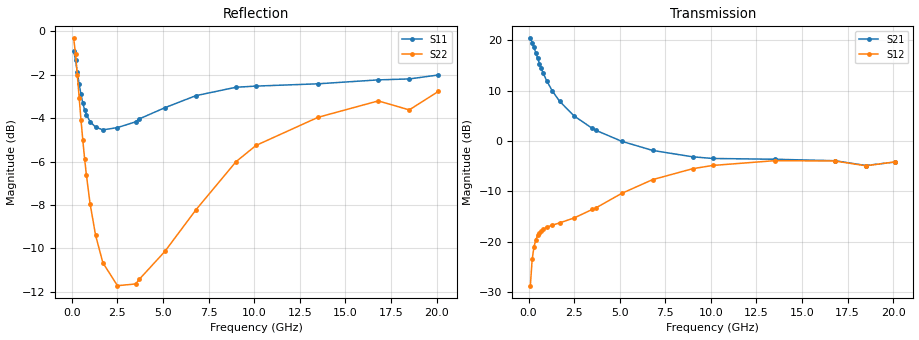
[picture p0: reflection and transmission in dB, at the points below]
!  Infineon Technologies AG
! BFR380L3 , PF131585-7, No.6, Th 09.10.01, soldered on pcb-board, measured with PP GSG850
!  Vce=1.0 V,  Ic=3.0 mA
! Common Emitter S-Parameters:  15. November 2001
#  GHz  S  MA  R  50
! f  S11  S21  S12  S22
! GHz  Mag  Ang  Mag  Ang  Mag  Ang  Mag  Ang
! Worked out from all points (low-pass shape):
!   201 points, 100 MHz to 20.1 GHz, reference 50 ohm
!   highest |S21| = 20.36 dB at 100 MHz (marker M1); lowest = -4.9 dB at 18.5 GHz (marker M2)
!   |S21| within 3 dB of the highest: start of sweep to 410.4 MHz
!   lowest |S11| = -4.5 dB at 1.7 GHz (marker M3), VSWR 3.91, Z = 12.9 - j4.18 ohm
!   |S11| at or under -10 dB: nowhere
!   |S22| runs from -11.9 to -0.3 dB; largest |S21 - S12| = 10
!   S11 on the Smith chart (normalised r, x): 100 MHz: 1.11, -4.38; 400 MHz: 0.31, -1.08; 1 GHz: 0.27, -0.35; 3.7 GHz: 0.25, +0.28; 9 GHz: 0.32, +1.05; 20.1 GHz: 0.98, +2.57
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0.1  0.9011 -24.3  10.42 163.8  0.03651 76.1  0.9634 -14.9
0.2  0.861 -46.6  9.474 149.3  0.06665 65.1  0.8882 -28.1
0.3  0.8053 -66.4  8.466 137.2  0.089 55.5  0.7937 -38.8
0.4  0.7552 -82.8  7.476 127.3  0.1044 48.4  0.7039 -47.2
0.5  0.7154 -96.4  6.595 119.2  0.1151 43.4  0.6259 -53.9
0.6  0.6836 -107.9  5.852 112.6  0.1231 39.7  0.5617 -59.1
0.7  0.6592 -117.6  5.244 106.9  0.1288 36.9  0.5088 -63.5
0.8  0.6428 -126.0  4.724 102.1  0.1328 35.0  0.4656 -67.1
1  0.6191 -139.4  3.941 94.1  0.139 32.6  0.4006 -73.0
1.3  0.6016 -154.9  3.144 84.4  0.1455 31.3  0.339 -80.0
1.7  0.5928 -169.8  2.48 74.1  0.1534 32.0  0.2929 -87.8
2.5  0.6 169.0  1.768 57.8  0.1717 36.3  0.2593 -102.4
3.5  0.6187 149.3  1.331 41.6  0.2088 41.9  0.2617 -121.1
3.7  0.6284 146.5  1.272 39.1  0.2164 42.4  0.2683 -125.7
5.1  0.6668 125.2  0.9923 22.3  0.3007 42.7  0.311 -152.1
6.8  0.7108 104.4  0.8043 8.8  0.4122 34.9  0.3877 176.8
8.999999  0.7433 84.3  0.6949 -1.6  0.5295 19.7  0.5006 145.7
10.1  0.7478 76.2  0.6692 -5.9  0.5703 11.7  0.5459 131.7
13.5  0.757 58.5  0.6571 -19.5  0.6363 -10.8  0.6337 98.7
16.8  0.7729 47.0  0.6355 -31.6  0.6315 -26.9  0.6913 76.1
18.5  0.7768 45.2  0.5694 -39.4  0.5663 -35.4  0.6591 70.4
20.1  0.7933 38.0  0.6168 -43.3  0.6189 -40.4  0.7271 59.6
